VERSION 5.8 ;
BUSBITCHARS "[]" ;
DIVIDERCHAR "/" ;
UNITS
    DATABASE MICRONS 2000 ;
END UNITS

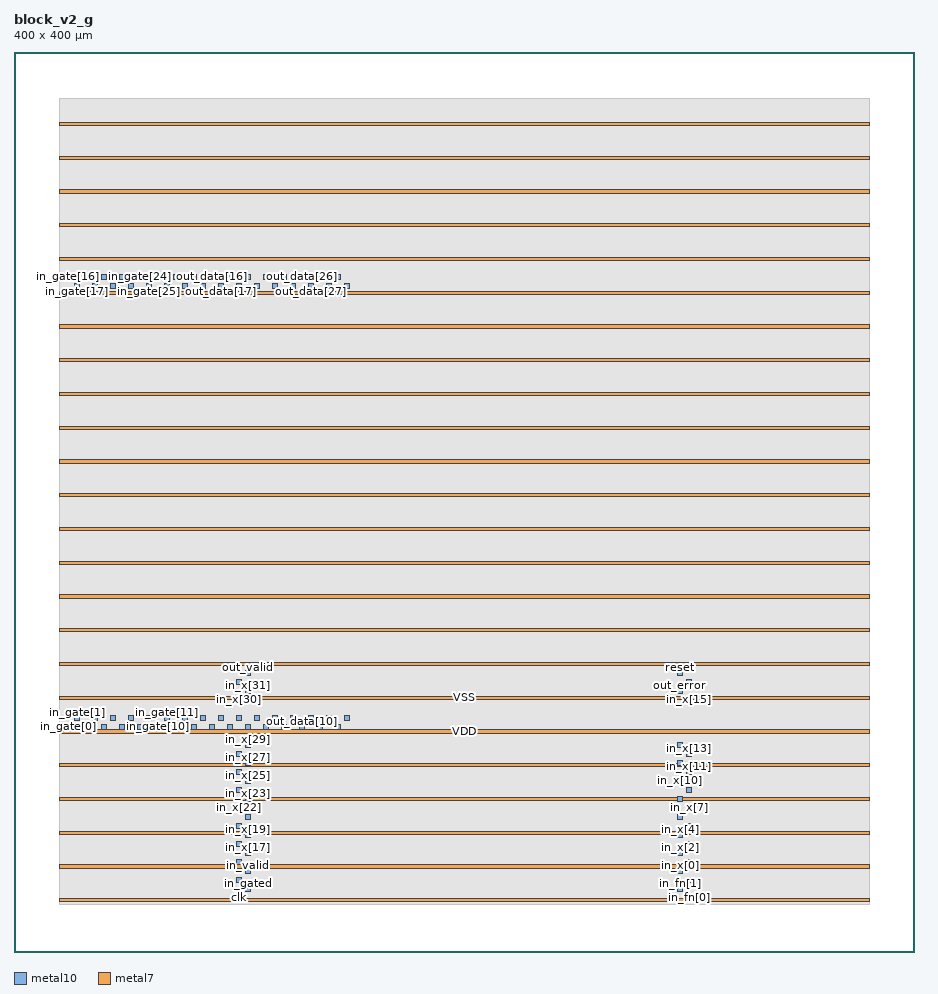
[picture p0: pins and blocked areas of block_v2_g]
MACRO block_v2_g
  FOREIGN block_v2_g 0 0 ;
  CLASS BLOCK ;
  SIZE 400 BY 400 ;
  PIN clk
    DIRECTION INPUT ;
    USE SIGNAL ;
    PORT
      LAYER metal10 ;
        RECT  99.095 23.07 101.095 25.07 ;
    END
  END clk
  PIN in_fn[0]
    DIRECTION INPUT ;
    USE SIGNAL ;
    PORT
      LAYER metal10 ;
        RECT  299.095 23.07 301.095 25.07 ;
    END
  END in_fn[0]
  PIN in_fn[1]
    DIRECTION INPUT ;
    USE SIGNAL ;
    PORT
      LAYER metal10 ;
        RECT  295.095 27.07 297.095 29.07 ;
    END
  END in_fn[1]
  PIN in_fn[2]
    DIRECTION INPUT ;
    USE SIGNAL ;
    PORT
      LAYER metal10 ;
        RECT  299.095 31.07 301.095 33.07 ;
    END
  END in_fn[2]
  PIN in_gate[0]
    DIRECTION INPUT ;
    USE SIGNAL ;
    PORT
      LAYER metal10 ;
        RECT  23.095 99.07 25.095 101.07 ;
    END
  END in_gate[0]
  PIN in_gate[10]
    DIRECTION INPUT ;
    USE SIGNAL ;
    PORT
      LAYER metal10 ;
        RECT  63.095 99.07 65.095 101.07 ;
    END
  END in_gate[10]
  PIN in_gate[11]
    DIRECTION INPUT ;
    USE SIGNAL ;
    PORT
      LAYER metal10 ;
        RECT  67.095 103.07 69.095 105.07 ;
    END
  END in_gate[11]
  PIN in_gate[12]
    DIRECTION INPUT ;
    USE SIGNAL ;
    PORT
      LAYER metal10 ;
        RECT  71.095 99.07 73.095 101.07 ;
    END
  END in_gate[12]
  PIN in_gate[13]
    DIRECTION INPUT ;
    USE SIGNAL ;
    PORT
      LAYER metal10 ;
        RECT  75.095 103.07 77.095 105.07 ;
    END
  END in_gate[13]
  PIN in_gate[14]
    DIRECTION INPUT ;
    USE SIGNAL ;
    PORT
      LAYER metal10 ;
        RECT  79.095 99.07 81.095 101.07 ;
    END
  END in_gate[14]
  PIN in_gate[15]
    DIRECTION INPUT ;
    USE SIGNAL ;
    PORT
      LAYER metal10 ;
        RECT  83.095 103.07 85.095 105.07 ;
    END
  END in_gate[15]
  PIN in_gate[16]
    DIRECTION INPUT ;
    USE SIGNAL ;
    PORT
      LAYER metal10 ;
        RECT  23.095 299.07 25.095 301.07 ;
    END
  END in_gate[16]
  PIN in_gate[17]
    DIRECTION INPUT ;
    USE SIGNAL ;
    PORT
      LAYER metal10 ;
        RECT  27.095 295.07 29.095 297.07 ;
    END
  END in_gate[17]
  PIN in_gate[18]
    DIRECTION INPUT ;
    USE SIGNAL ;
    PORT
      LAYER metal10 ;
        RECT  31.095 299.07 33.095 301.07 ;
    END
  END in_gate[18]
  PIN in_gate[19]
    DIRECTION INPUT ;
    USE SIGNAL ;
    PORT
      LAYER metal10 ;
        RECT  35.095 295.07 37.095 297.07 ;
    END
  END in_gate[19]
  PIN in_gate[1]
    DIRECTION INPUT ;
    USE SIGNAL ;
    PORT
      LAYER metal10 ;
        RECT  27.095 103.07 29.095 105.07 ;
    END
  END in_gate[1]
  PIN in_gate[20]
    DIRECTION INPUT ;
    USE SIGNAL ;
    PORT
      LAYER metal10 ;
        RECT  39.095 299.07 41.095 301.07 ;
    END
  END in_gate[20]
  PIN in_gate[21]
    DIRECTION INPUT ;
    USE SIGNAL ;
    PORT
      LAYER metal10 ;
        RECT  43.095 295.07 45.095 297.07 ;
    END
  END in_gate[21]
  PIN in_gate[22]
    DIRECTION INPUT ;
    USE SIGNAL ;
    PORT
      LAYER metal10 ;
        RECT  47.095 299.07 49.095 301.07 ;
    END
  END in_gate[22]
  PIN in_gate[23]
    DIRECTION INPUT ;
    USE SIGNAL ;
    PORT
      LAYER metal10 ;
        RECT  51.095 295.07 53.095 297.07 ;
    END
  END in_gate[23]
  PIN in_gate[24]
    DIRECTION INPUT ;
    USE SIGNAL ;
    PORT
      LAYER metal10 ;
        RECT  55.095 299.07 57.095 301.07 ;
    END
  END in_gate[24]
  PIN in_gate[25]
    DIRECTION INPUT ;
    USE SIGNAL ;
    PORT
      LAYER metal10 ;
        RECT  59.095 295.07 61.095 297.07 ;
    END
  END in_gate[25]
  PIN in_gate[26]
    DIRECTION INPUT ;
    USE SIGNAL ;
    PORT
      LAYER metal10 ;
        RECT  63.095 299.07 65.095 301.07 ;
    END
  END in_gate[26]
  PIN in_gate[27]
    DIRECTION INPUT ;
    USE SIGNAL ;
    PORT
      LAYER metal10 ;
        RECT  67.095 295.07 69.095 297.07 ;
    END
  END in_gate[27]
  PIN in_gate[28]
    DIRECTION INPUT ;
    USE SIGNAL ;
    PORT
      LAYER metal10 ;
        RECT  71.095 299.07 73.095 301.07 ;
    END
  END in_gate[28]
  PIN in_gate[29]
    DIRECTION INPUT ;
    USE SIGNAL ;
    PORT
      LAYER metal10 ;
        RECT  75.095 295.07 77.095 297.07 ;
    END
  END in_gate[29]
  PIN in_gate[2]
    DIRECTION INPUT ;
    USE SIGNAL ;
    PORT
      LAYER metal10 ;
        RECT  31.095 99.07 33.095 101.07 ;
    END
  END in_gate[2]
  PIN in_gate[30]
    DIRECTION INPUT ;
    USE SIGNAL ;
    PORT
      LAYER metal10 ;
        RECT  79.095 299.07 81.095 301.07 ;
    END
  END in_gate[30]
  PIN in_gate[31]
    DIRECTION INPUT ;
    USE SIGNAL ;
    PORT
      LAYER metal10 ;
        RECT  83.095 295.07 85.095 297.07 ;
    END
  END in_gate[31]
  PIN in_gate[3]
    DIRECTION INPUT ;
    USE SIGNAL ;
    PORT
      LAYER metal10 ;
        RECT  35.095 103.07 37.095 105.07 ;
    END
  END in_gate[3]
  PIN in_gate[4]
    DIRECTION INPUT ;
    USE SIGNAL ;
    PORT
      LAYER metal10 ;
        RECT  39.095 99.07 41.095 101.07 ;
    END
  END in_gate[4]
  PIN in_gate[5]
    DIRECTION INPUT ;
    USE SIGNAL ;
    PORT
      LAYER metal10 ;
        RECT  43.095 103.07 45.095 105.07 ;
    END
  END in_gate[5]
  PIN in_gate[6]
    DIRECTION INPUT ;
    USE SIGNAL ;
    PORT
      LAYER metal10 ;
        RECT  47.095 99.07 49.095 101.07 ;
    END
  END in_gate[6]
  PIN in_gate[7]
    DIRECTION INPUT ;
    USE SIGNAL ;
    PORT
      LAYER metal10 ;
        RECT  51.095 103.07 53.095 105.07 ;
    END
  END in_gate[7]
  PIN in_gate[8]
    DIRECTION INPUT ;
    USE SIGNAL ;
    PORT
      LAYER metal10 ;
        RECT  55.095 99.07 57.095 101.07 ;
    END
  END in_gate[8]
  PIN in_gate[9]
    DIRECTION INPUT ;
    USE SIGNAL ;
    PORT
      LAYER metal10 ;
        RECT  59.095 103.07 61.095 105.07 ;
    END
  END in_gate[9]
  PIN in_gated
    DIRECTION INPUT ;
    USE SIGNAL ;
    PORT
      LAYER metal10 ;
        RECT  103.095 27.07 105.095 29.07 ;
    END
  END in_gated
  PIN in_ready
    DIRECTION OUTPUT ;
    USE SIGNAL ;
    PORT
      LAYER metal10 ;
        RECT  99.095 31.07 101.095 33.07 ;
    END
  END in_ready
  PIN in_valid
    DIRECTION INPUT ;
    USE SIGNAL ;
    PORT
      LAYER metal10 ;
        RECT  103.095 35.07 105.095 37.07 ;
    END
  END in_valid
  PIN in_x[0]
    DIRECTION INPUT ;
    USE SIGNAL ;
    PORT
      LAYER metal10 ;
        RECT  295.095 35.07 297.095 37.07 ;
    END
  END in_x[0]
  PIN in_x[10]
    DIRECTION INPUT ;
    USE SIGNAL ;
    PORT
      LAYER metal10 ;
        RECT  295.095 75.07 297.095 77.07 ;
    END
  END in_x[10]
  PIN in_x[11]
    DIRECTION INPUT ;
    USE SIGNAL ;
    PORT
      LAYER metal10 ;
        RECT  299.095 79.07 301.095 81.07 ;
    END
  END in_x[11]
  PIN in_x[12]
    DIRECTION INPUT ;
    USE SIGNAL ;
    PORT
      LAYER metal10 ;
        RECT  295.095 83.07 297.095 85.07 ;
    END
  END in_x[12]
  PIN in_x[13]
    DIRECTION INPUT ;
    USE SIGNAL ;
    PORT
      LAYER metal10 ;
        RECT  299.095 87.07 301.095 89.07 ;
    END
  END in_x[13]
  PIN in_x[14]
    DIRECTION INPUT ;
    USE SIGNAL ;
    PORT
      LAYER metal10 ;
        RECT  295.095 91.07 297.095 93.07 ;
    END
  END in_x[14]
  PIN in_x[15]
    DIRECTION INPUT ;
    USE SIGNAL ;
    PORT
      LAYER metal10 ;
        RECT  299.095 111.07 301.095 113.07 ;
    END
  END in_x[15]
  PIN in_x[16]
    DIRECTION INPUT ;
    USE SIGNAL ;
    PORT
      LAYER metal10 ;
        RECT  99.095 39.07 101.095 41.07 ;
    END
  END in_x[16]
  PIN in_x[17]
    DIRECTION INPUT ;
    USE SIGNAL ;
    PORT
      LAYER metal10 ;
        RECT  103.095 43.07 105.095 45.07 ;
    END
  END in_x[17]
  PIN in_x[18]
    DIRECTION INPUT ;
    USE SIGNAL ;
    PORT
      LAYER metal10 ;
        RECT  99.095 47.07 101.095 49.07 ;
    END
  END in_x[18]
  PIN in_x[19]
    DIRECTION INPUT ;
    USE SIGNAL ;
    PORT
      LAYER metal10 ;
        RECT  103.095 51.07 105.095 53.07 ;
    END
  END in_x[19]
  PIN in_x[1]
    DIRECTION INPUT ;
    USE SIGNAL ;
    PORT
      LAYER metal10 ;
        RECT  299.095 39.07 301.095 41.07 ;
    END
  END in_x[1]
  PIN in_x[20]
    DIRECTION INPUT ;
    USE SIGNAL ;
    PORT
      LAYER metal10 ;
        RECT  99.095 55.07 101.095 57.07 ;
    END
  END in_x[20]
  PIN in_x[21]
    DIRECTION INPUT ;
    USE SIGNAL ;
    PORT
      LAYER metal10 ;
        RECT  103.095 59.07 105.095 61.07 ;
    END
  END in_x[21]
  PIN in_x[22]
    DIRECTION INPUT ;
    USE SIGNAL ;
    PORT
      LAYER metal10 ;
        RECT  99.095 63.07 101.095 65.07 ;
    END
  END in_x[22]
  PIN in_x[23]
    DIRECTION INPUT ;
    USE SIGNAL ;
    PORT
      LAYER metal10 ;
        RECT  103.095 67.07 105.095 69.07 ;
    END
  END in_x[23]
  PIN in_x[24]
    DIRECTION INPUT ;
    USE SIGNAL ;
    PORT
      LAYER metal10 ;
        RECT  99.095 71.07 101.095 73.07 ;
    END
  END in_x[24]
  PIN in_x[25]
    DIRECTION INPUT ;
    USE SIGNAL ;
    PORT
      LAYER metal10 ;
        RECT  103.095 75.07 105.095 77.07 ;
    END
  END in_x[25]
  PIN in_x[26]
    DIRECTION INPUT ;
    USE SIGNAL ;
    PORT
      LAYER metal10 ;
        RECT  99.095 79.07 101.095 81.07 ;
    END
  END in_x[26]
  PIN in_x[27]
    DIRECTION INPUT ;
    USE SIGNAL ;
    PORT
      LAYER metal10 ;
        RECT  103.095 83.07 105.095 85.07 ;
    END
  END in_x[27]
  PIN in_x[28]
    DIRECTION INPUT ;
    USE SIGNAL ;
    PORT
      LAYER metal10 ;
        RECT  99.095 87.07 101.095 89.07 ;
    END
  END in_x[28]
  PIN in_x[29]
    DIRECTION INPUT ;
    USE SIGNAL ;
    PORT
      LAYER metal10 ;
        RECT  103.095 91.07 105.095 93.07 ;
    END
  END in_x[29]
  PIN in_x[2]
    DIRECTION INPUT ;
    USE SIGNAL ;
    PORT
      LAYER metal10 ;
        RECT  295.095 43.07 297.095 45.07 ;
    END
  END in_x[2]
  PIN in_x[30]
    DIRECTION INPUT ;
    USE SIGNAL ;
    PORT
      LAYER metal10 ;
        RECT  99.095 111.07 101.095 113.07 ;
    END
  END in_x[30]
  PIN in_x[31]
    DIRECTION INPUT ;
    USE SIGNAL ;
    PORT
      LAYER metal10 ;
        RECT  103.095 115.07 105.095 117.07 ;
    END
  END in_x[31]
  PIN in_x[3]
    DIRECTION INPUT ;
    USE SIGNAL ;
    PORT
      LAYER metal10 ;
        RECT  299.095 47.07 301.095 49.07 ;
    END
  END in_x[3]
  PIN in_x[4]
    DIRECTION INPUT ;
    USE SIGNAL ;
    PORT
      LAYER metal10 ;
        RECT  295.095 51.07 297.095 53.07 ;
    END
  END in_x[4]
  PIN in_x[5]
    DIRECTION INPUT ;
    USE SIGNAL ;
    PORT
      LAYER metal10 ;
        RECT  299.095 55.07 301.095 57.07 ;
    END
  END in_x[5]
  PIN in_x[6]
    DIRECTION INPUT ;
    USE SIGNAL ;
    PORT
      LAYER metal10 ;
        RECT  295.095 59.07 297.095 61.07 ;
    END
  END in_x[6]
  PIN in_x[7]
    DIRECTION INPUT ;
    USE SIGNAL ;
    PORT
      LAYER metal10 ;
        RECT  299.095 63.07 301.095 65.07 ;
    END
  END in_x[7]
  PIN in_x[8]
    DIRECTION INPUT ;
    USE SIGNAL ;
    PORT
      LAYER metal10 ;
        RECT  295.095 67.07 297.095 69.07 ;
    END
  END in_x[8]
  PIN in_x[9]
    DIRECTION INPUT ;
    USE SIGNAL ;
    PORT
      LAYER metal10 ;
        RECT  299.095 71.07 301.095 73.07 ;
    END
  END in_x[9]
  PIN out_data[0]
    DIRECTION OUTPUT ;
    USE SIGNAL ;
    PORT
      LAYER metal10 ;
        RECT  87.095 99.07 89.095 101.07 ;
    END
  END out_data[0]
  PIN out_data[10]
    DIRECTION OUTPUT ;
    USE SIGNAL ;
    PORT
      LAYER metal10 ;
        RECT  127.095 99.07 129.095 101.07 ;
    END
  END out_data[10]
  PIN out_data[11]
    DIRECTION OUTPUT ;
    USE SIGNAL ;
    PORT
      LAYER metal10 ;
        RECT  131.095 103.07 133.095 105.07 ;
    END
  END out_data[11]
  PIN out_data[12]
    DIRECTION OUTPUT ;
    USE SIGNAL ;
    PORT
      LAYER metal10 ;
        RECT  135.095 99.07 137.095 101.07 ;
    END
  END out_data[12]
  PIN out_data[13]
    DIRECTION OUTPUT ;
    USE SIGNAL ;
    PORT
      LAYER metal10 ;
        RECT  139.095 103.07 141.095 105.07 ;
    END
  END out_data[13]
  PIN out_data[14]
    DIRECTION OUTPUT ;
    USE SIGNAL ;
    PORT
      LAYER metal10 ;
        RECT  143.095 99.07 145.095 101.07 ;
    END
  END out_data[14]
  PIN out_data[15]
    DIRECTION OUTPUT ;
    USE SIGNAL ;
    PORT
      LAYER metal10 ;
        RECT  147.095 103.07 149.095 105.07 ;
    END
  END out_data[15]
  PIN out_data[16]
    DIRECTION OUTPUT ;
    USE SIGNAL ;
    PORT
      LAYER metal10 ;
        RECT  87.095 299.07 89.095 301.07 ;
    END
  END out_data[16]
  PIN out_data[17]
    DIRECTION OUTPUT ;
    USE SIGNAL ;
    PORT
      LAYER metal10 ;
        RECT  91.095 295.07 93.095 297.07 ;
    END
  END out_data[17]
  PIN out_data[18]
    DIRECTION OUTPUT ;
    USE SIGNAL ;
    PORT
      LAYER metal10 ;
        RECT  95.095 299.07 97.095 301.07 ;
    END
  END out_data[18]
  PIN out_data[19]
    DIRECTION OUTPUT ;
    USE SIGNAL ;
    PORT
      LAYER metal10 ;
        RECT  99.095 295.07 101.095 297.07 ;
    END
  END out_data[19]
  PIN out_data[1]
    DIRECTION OUTPUT ;
    USE SIGNAL ;
    PORT
      LAYER metal10 ;
        RECT  91.095 103.07 93.095 105.07 ;
    END
  END out_data[1]
  PIN out_data[20]
    DIRECTION OUTPUT ;
    USE SIGNAL ;
    PORT
      LAYER metal10 ;
        RECT  103.095 299.07 105.095 301.07 ;
    END
  END out_data[20]
  PIN out_data[21]
    DIRECTION OUTPUT ;
    USE SIGNAL ;
    PORT
      LAYER metal10 ;
        RECT  107.095 295.07 109.095 297.07 ;
    END
  END out_data[21]
  PIN out_data[22]
    DIRECTION OUTPUT ;
    USE SIGNAL ;
    PORT
      LAYER metal10 ;
        RECT  111.095 299.07 113.095 301.07 ;
    END
  END out_data[22]
  PIN out_data[23]
    DIRECTION OUTPUT ;
    USE SIGNAL ;
    PORT
      LAYER metal10 ;
        RECT  115.095 295.07 117.095 297.07 ;
    END
  END out_data[23]
  PIN out_data[24]
    DIRECTION OUTPUT ;
    USE SIGNAL ;
    PORT
      LAYER metal10 ;
        RECT  119.095 299.07 121.095 301.07 ;
    END
  END out_data[24]
  PIN out_data[25]
    DIRECTION OUTPUT ;
    USE SIGNAL ;
    PORT
      LAYER metal10 ;
        RECT  123.095 295.07 125.095 297.07 ;
    END
  END out_data[25]
  PIN out_data[26]
    DIRECTION OUTPUT ;
    USE SIGNAL ;
    PORT
      LAYER metal10 ;
        RECT  127.095 299.07 129.095 301.07 ;
    END
  END out_data[26]
  PIN out_data[27]
    DIRECTION OUTPUT ;
    USE SIGNAL ;
    PORT
      LAYER metal10 ;
        RECT  131.095 295.07 133.095 297.07 ;
    END
  END out_data[27]
  PIN out_data[28]
    DIRECTION OUTPUT ;
    USE SIGNAL ;
    PORT
      LAYER metal10 ;
        RECT  135.095 299.07 137.095 301.07 ;
    END
  END out_data[28]
  PIN out_data[29]
    DIRECTION OUTPUT ;
    USE SIGNAL ;
    PORT
      LAYER metal10 ;
        RECT  139.095 295.07 141.095 297.07 ;
    END
  END out_data[29]
  PIN out_data[2]
    DIRECTION OUTPUT ;
    USE SIGNAL ;
    PORT
      LAYER metal10 ;
        RECT  95.095 99.07 97.095 101.07 ;
    END
  END out_data[2]
  PIN out_data[30]
    DIRECTION OUTPUT ;
    USE SIGNAL ;
    PORT
      LAYER metal10 ;
        RECT  143.095 299.07 145.095 301.07 ;
    END
  END out_data[30]
  PIN out_data[31]
    DIRECTION OUTPUT ;
    USE SIGNAL ;
    PORT
      LAYER metal10 ;
        RECT  147.095 295.07 149.095 297.07 ;
    END
  END out_data[31]
  PIN out_data[3]
    DIRECTION OUTPUT ;
    USE SIGNAL ;
    PORT
      LAYER metal10 ;
        RECT  99.095 103.07 101.095 105.07 ;
    END
  END out_data[3]
  PIN out_data[4]
    DIRECTION OUTPUT ;
    USE SIGNAL ;
    PORT
      LAYER metal10 ;
        RECT  103.095 99.07 105.095 101.07 ;
    END
  END out_data[4]
  PIN out_data[5]
    DIRECTION OUTPUT ;
    USE SIGNAL ;
    PORT
      LAYER metal10 ;
        RECT  107.095 103.07 109.095 105.07 ;
    END
  END out_data[5]
  PIN out_data[6]
    DIRECTION OUTPUT ;
    USE SIGNAL ;
    PORT
      LAYER metal10 ;
        RECT  111.095 99.07 113.095 101.07 ;
    END
  END out_data[6]
  PIN out_data[7]
    DIRECTION OUTPUT ;
    USE SIGNAL ;
    PORT
      LAYER metal10 ;
        RECT  115.095 103.07 117.095 105.07 ;
    END
  END out_data[7]
  PIN out_data[8]
    DIRECTION OUTPUT ;
    USE SIGNAL ;
    PORT
      LAYER metal10 ;
        RECT  119.095 99.07 121.095 101.07 ;
    END
  END out_data[8]
  PIN out_data[9]
    DIRECTION OUTPUT ;
    USE SIGNAL ;
    PORT
      LAYER metal10 ;
        RECT  123.095 103.07 125.095 105.07 ;
    END
  END out_data[9]
  PIN out_error
    DIRECTION OUTPUT ;
    USE SIGNAL ;
    PORT
      LAYER metal10 ;
        RECT  295.095 115.07 297.095 117.07 ;
    END
  END out_error
  PIN out_ready
    DIRECTION INPUT ;
    USE SIGNAL ;
    PORT
      LAYER metal10 ;
        RECT  99.095 119.07 101.095 121.07 ;
    END
  END out_ready
  PIN out_saturated
    DIRECTION OUTPUT ;
    USE SIGNAL ;
    PORT
      LAYER metal10 ;
        RECT  299.095 119.07 301.095 121.07 ;
    END
  END out_saturated
  PIN out_valid
    DIRECTION OUTPUT ;
    USE SIGNAL ;
    PORT
      LAYER metal10 ;
        RECT  103.095 123.07 105.095 125.07 ;
    END
  END out_valid
  PIN reset
    DIRECTION INPUT ;
    USE SIGNAL ;
    PORT
      LAYER metal10 ;
        RECT  295.095 123.07 297.095 125.07 ;
    END
  END reset
  PIN VSS
    DIRECTION INOUT ;
    USE GROUND ;
    PORT
      LAYER metal7 ;
        RECT  20.14 352.3 380 353.7 ;
        RECT  20.14 322.3 380 323.7 ;
        RECT  20.14 292.3 380 293.7 ;
        RECT  20.14 262.3 380 263.7 ;
        RECT  20.14 232.3 380 233.7 ;
        RECT  20.14 202.3 380 203.7 ;
        RECT  20.14 172.3 380 173.7 ;
        RECT  20.14 142.3 380 143.7 ;
        RECT  20.14 112.3 380 113.7 ;
        RECT  20.14 82.3 380 83.7 ;
        RECT  20.14 52.3 380 53.7 ;
        RECT  20.14 22.3 380 23.7 ;
    END
  END VSS
  PIN VDD
    DIRECTION INOUT ;
    USE POWER ;
    PORT
      LAYER metal7 ;
        RECT  20.14 367.3 380 368.7 ;
        RECT  20.14 337.3 380 338.7 ;
        RECT  20.14 307.3 380 308.7 ;
        RECT  20.14 277.3 380 278.7 ;
        RECT  20.14 247.3 380 248.7 ;
        RECT  20.14 217.3 380 218.7 ;
        RECT  20.14 187.3 380 188.7 ;
        RECT  20.14 157.3 380 158.7 ;
        RECT  20.14 127.3 380 128.7 ;
        RECT  20.14 97.3 380 98.7 ;
        RECT  20.14 67.3 380 68.7 ;
        RECT  20.14 37.3 380 38.7 ;
    END
  END VDD
  OBS
    LAYER metal1 ;
     RECT  20.14 20.915 380 379.485 ;
    LAYER metal2 ;
     RECT  20.14 20.915 380 379.485 ;
    LAYER metal3 ;
     RECT  20.14 20.915 380 379.485 ;
    LAYER metal4 ;
     RECT  20.14 20.915 380 379.485 ;
    LAYER metal5 ;
     RECT  20.14 20.915 380 379.485 ;
    LAYER metal6 ;
     RECT  20.14 20.915 380 379.485 ;
    LAYER metal7 ;
     RECT  20.14 20.915 380 379.485 ;
    LAYER metal8 ;
     RECT  20.14 20.915 380 379.485 ;
    LAYER metal9 ;
     RECT  20.14 20.915 380 379.485 ;
    LAYER metal10 ;
     RECT  20.14 20.915 380 379.485 ;
  END
END block_v2_g
END LIBRARY
